VERSION 5.4 ;
NAMESCASESENSITIVE ON ;
BUSBITCHARS "[]" ;
DIVIDERCHAR "/" ;
UNITS
  DATABASE MICRONS 2000 ;
END UNITS
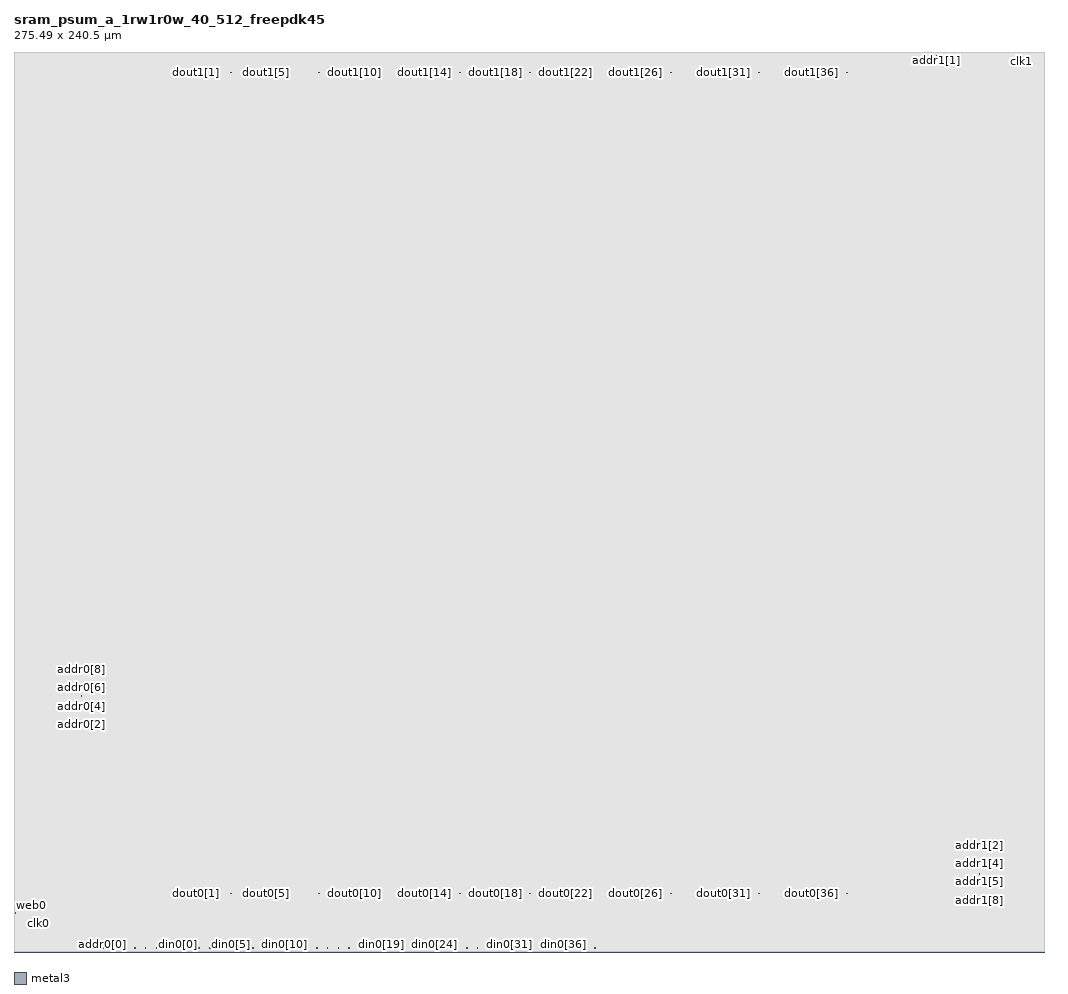
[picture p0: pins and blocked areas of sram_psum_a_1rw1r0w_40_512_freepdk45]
MACRO sram_psum_a_1rw1r0w_40_512_freepdk45
   CLASS BLOCK ;
   SIZE 275.49 BY 240.5 ;
   SYMMETRY X Y R90 ;
   PIN din0[0]
      DIRECTION INPUT ;
      PORT
         LAYER metal3 ;
         RECT 43.715 1.04 43.85 1.175 ;
      END
   END din0[0]
   PIN din0[1]
      DIRECTION INPUT ;
      PORT
         LAYER metal3 ;
         RECT 46.575 1.04 46.71 1.175 ;
      END
   END din0[1]
   PIN din0[2]
      DIRECTION INPUT ;
      PORT
         LAYER metal3 ;
         RECT 49.435 1.04 49.57 1.175 ;
      END
   END din0[2]
   PIN din0[3]
      DIRECTION INPUT ;
      PORT
         LAYER metal3 ;
         RECT 52.295 1.04 52.43 1.175 ;
      END
   END din0[3]
   PIN din0[4]
      DIRECTION INPUT ;
      PORT
         LAYER metal3 ;
         RECT 55.155 1.04 55.29 1.175 ;
      END
   END din0[4]
   PIN din0[5]
      DIRECTION INPUT ;
      PORT
         LAYER metal3 ;
         RECT 58.015 1.04 58.15 1.175 ;
      END
   END din0[5]
   PIN din0[6]
      DIRECTION INPUT ;
      PORT
         LAYER metal3 ;
         RECT 60.875 1.04 61.01 1.175 ;
      END
   END din0[6]
   PIN din0[7]
      DIRECTION INPUT ;
      PORT
         LAYER metal3 ;
         RECT 63.735 1.04 63.87 1.175 ;
      END
   END din0[7]
   PIN din0[8]
      DIRECTION INPUT ;
      PORT
         LAYER metal3 ;
         RECT 66.595 1.04 66.73 1.175 ;
      END
   END din0[8]
   PIN din0[9]
      DIRECTION INPUT ;
      PORT
         LAYER metal3 ;
         RECT 69.455 1.04 69.59 1.175 ;
      END
   END din0[9]
   PIN din0[10]
      DIRECTION INPUT ;
      PORT
         LAYER metal3 ;
         RECT 72.315 1.04 72.45 1.175 ;
      END
   END din0[10]
   PIN din0[11]
      DIRECTION INPUT ;
      PORT
         LAYER metal3 ;
         RECT 75.175 1.04 75.31 1.175 ;
      END
   END din0[11]
   PIN din0[12]
      DIRECTION INPUT ;
      PORT
         LAYER metal3 ;
         RECT 78.035 1.04 78.17 1.175 ;
      END
   END din0[12]
   PIN din0[13]
      DIRECTION INPUT ;
      PORT
         LAYER metal3 ;
         RECT 80.895 1.04 81.03 1.175 ;
      END
   END din0[13]
   PIN din0[14]
      DIRECTION INPUT ;
      PORT
         LAYER metal3 ;
         RECT 83.755 1.04 83.89 1.175 ;
      END
   END din0[14]
   PIN din0[15]
      DIRECTION INPUT ;
      PORT
         LAYER metal3 ;
         RECT 86.615 1.04 86.75 1.175 ;
      END
   END din0[15]
   PIN din0[16]
      DIRECTION INPUT ;
      PORT
         LAYER metal3 ;
         RECT 89.475 1.04 89.61 1.175 ;
      END
   END din0[16]
   PIN din0[17]
      DIRECTION INPUT ;
      PORT
         LAYER metal3 ;
         RECT 92.335 1.04 92.47 1.175 ;
      END
   END din0[17]
   PIN din0[18]
      DIRECTION INPUT ;
      PORT
         LAYER metal3 ;
         RECT 95.195 1.04 95.33 1.175 ;
      END
   END din0[18]
   PIN din0[19]
      DIRECTION INPUT ;
      PORT
         LAYER metal3 ;
         RECT 98.055 1.04 98.19 1.175 ;
      END
   END din0[19]
   PIN din0[20]
      DIRECTION INPUT ;
      PORT
         LAYER metal3 ;
         RECT 100.915 1.04 101.05 1.175 ;
      END
   END din0[20]
   PIN din0[21]
      DIRECTION INPUT ;
      PORT
         LAYER metal3 ;
         RECT 103.775 1.04 103.91 1.175 ;
      END
   END din0[21]
   PIN din0[22]
      DIRECTION INPUT ;
      PORT
         LAYER metal3 ;
         RECT 106.635 1.04 106.77 1.175 ;
      END
   END din0[22]
   PIN din0[23]
      DIRECTION INPUT ;
      PORT
         LAYER metal3 ;
         RECT 109.495 1.04 109.63 1.175 ;
      END
   END din0[23]
   PIN din0[24]
      DIRECTION INPUT ;
      PORT
         LAYER metal3 ;
         RECT 112.355 1.04 112.49 1.175 ;
      END
   END din0[24]
   PIN din0[25]
      DIRECTION INPUT ;
      PORT
         LAYER metal3 ;
         RECT 115.215 1.04 115.35 1.175 ;
      END
   END din0[25]
   PIN din0[26]
      DIRECTION INPUT ;
      PORT
         LAYER metal3 ;
         RECT 118.075 1.04 118.21 1.175 ;
      END
   END din0[26]
   PIN din0[27]
      DIRECTION INPUT ;
      PORT
         LAYER metal3 ;
         RECT 120.935 1.04 121.07 1.175 ;
      END
   END din0[27]
   PIN din0[28]
      DIRECTION INPUT ;
      PORT
         LAYER metal3 ;
         RECT 123.795 1.04 123.93 1.175 ;
      END
   END din0[28]
   PIN din0[29]
      DIRECTION INPUT ;
      PORT
         LAYER metal3 ;
         RECT 126.655 1.04 126.79 1.175 ;
      END
   END din0[29]
   PIN din0[30]
      DIRECTION INPUT ;
      PORT
         LAYER metal3 ;
         RECT 129.515 1.04 129.65 1.175 ;
      END
   END din0[30]
   PIN din0[31]
      DIRECTION INPUT ;
      PORT
         LAYER metal3 ;
         RECT 132.375 1.04 132.51 1.175 ;
      END
   END din0[31]
   PIN din0[32]
      DIRECTION INPUT ;
      PORT
         LAYER metal3 ;
         RECT 135.235 1.04 135.37 1.175 ;
      END
   END din0[32]
   PIN din0[33]
      DIRECTION INPUT ;
      PORT
         LAYER metal3 ;
         RECT 138.095 1.04 138.23 1.175 ;
      END
   END din0[33]
   PIN din0[34]
      DIRECTION INPUT ;
      PORT
         LAYER metal3 ;
         RECT 140.955 1.04 141.09 1.175 ;
      END
   END din0[34]
   PIN din0[35]
      DIRECTION INPUT ;
      PORT
         LAYER metal3 ;
         RECT 143.815 1.04 143.95 1.175 ;
      END
   END din0[35]
   PIN din0[36]
      DIRECTION INPUT ;
      PORT
         LAYER metal3 ;
         RECT 146.675 1.04 146.81 1.175 ;
      END
   END din0[36]
   PIN din0[37]
      DIRECTION INPUT ;
      PORT
         LAYER metal3 ;
         RECT 149.535 1.04 149.67 1.175 ;
      END
   END din0[37]
   PIN din0[38]
      DIRECTION INPUT ;
      PORT
         LAYER metal3 ;
         RECT 152.395 1.04 152.53 1.175 ;
      END
   END din0[38]
   PIN din0[39]
      DIRECTION INPUT ;
      PORT
         LAYER metal3 ;
         RECT 155.255 1.04 155.39 1.175 ;
      END
   END din0[39]
   PIN addr0[0]
      DIRECTION INPUT ;
      PORT
         LAYER metal3 ;
         RECT 23.695 1.04 23.83 1.175 ;
      END
   END addr0[0]
   PIN addr0[1]
      DIRECTION INPUT ;
      PORT
         LAYER metal3 ;
         RECT 26.555 1.04 26.69 1.175 ;
      END
   END addr0[1]
   PIN addr0[2]
      DIRECTION INPUT ;
      PORT
         LAYER metal3 ;
         RECT 17.975 60.615 18.11 60.75 ;
      END
   END addr0[2]
   PIN addr0[3]
      DIRECTION INPUT ;
      PORT
         LAYER metal3 ;
         RECT 17.975 63.345 18.11 63.48 ;
      END
   END addr0[3]
   PIN addr0[4]
      DIRECTION INPUT ;
      PORT
         LAYER metal3 ;
         RECT 17.975 65.555 18.11 65.69 ;
      END
   END addr0[4]
   PIN addr0[5]
      DIRECTION INPUT ;
      PORT
         LAYER metal3 ;
         RECT 17.975 68.285 18.11 68.42 ;
      END
   END addr0[5]
   PIN addr0[6]
      DIRECTION INPUT ;
      PORT
         LAYER metal3 ;
         RECT 17.975 70.495 18.11 70.63 ;
      END
   END addr0[6]
   PIN addr0[7]
      DIRECTION INPUT ;
      PORT
         LAYER metal3 ;
         RECT 17.975 73.225 18.11 73.36 ;
      END
   END addr0[7]
   PIN addr0[8]
      DIRECTION INPUT ;
      PORT
         LAYER metal3 ;
         RECT 17.975 75.435 18.11 75.57 ;
      END
   END addr0[8]
   PIN addr1[0]
      DIRECTION INPUT ;
      PORT
         LAYER metal3 ;
         RECT 249.355 239.33 249.49 239.465 ;
      END
   END addr1[0]
   PIN addr1[1]
      DIRECTION INPUT ;
      PORT
         LAYER metal3 ;
         RECT 246.495 239.33 246.63 239.465 ;
      END
   END addr1[1]
   PIN addr1[2]
      DIRECTION INPUT ;
      PORT
         LAYER metal3 ;
         RECT 257.935 28.505 258.07 28.64 ;
      END
   END addr1[2]
   PIN addr1[3]
      DIRECTION INPUT ;
      PORT
         LAYER metal3 ;
         RECT 257.935 25.775 258.07 25.91 ;
      END
   END addr1[3]
   PIN addr1[4]
      DIRECTION INPUT ;
      PORT
         LAYER metal3 ;
         RECT 257.935 23.565 258.07 23.7 ;
      END
   END addr1[4]
   PIN addr1[5]
      DIRECTION INPUT ;
      PORT
         LAYER metal3 ;
         RECT 257.935 20.835 258.07 20.97 ;
      END
   END addr1[5]
   PIN addr1[6]
      DIRECTION INPUT ;
      PORT
         LAYER metal3 ;
         RECT 257.935 18.625 258.07 18.76 ;
      END
   END addr1[6]
   PIN addr1[7]
      DIRECTION INPUT ;
      PORT
         LAYER metal3 ;
         RECT 257.935 15.895 258.07 16.03 ;
      END
   END addr1[7]
   PIN addr1[8]
      DIRECTION INPUT ;
      PORT
         LAYER metal3 ;
         RECT 257.935 13.685 258.07 13.82 ;
      END
   END addr1[8]
   PIN csb0
      DIRECTION INPUT ;
      PORT
         LAYER metal3 ;
         RECT 0.285 7.575 0.42 7.71 ;
      END
   END csb0
   PIN csb1
      DIRECTION INPUT ;
      PORT
         LAYER metal3 ;
         RECT 275.07 237.885 275.205 238.02 ;
      END
   END csb1
   PIN web0
      DIRECTION INPUT ;
      PORT
         LAYER metal3 ;
         RECT 0.285 10.305 0.42 10.44 ;
      END
   END web0
   PIN clk0
      DIRECTION INPUT ;
      PORT
         LAYER metal3 ;
         RECT 6.53 7.66 6.66 7.795 ;
      END
   END clk0
   PIN clk1
      DIRECTION INPUT ;
      PORT
         LAYER metal3 ;
         RECT 269.11 237.8 269.24 237.935 ;
      END
   END clk1
   PIN wmask0[0]
      DIRECTION INPUT ;
      PORT
         LAYER metal3 ;
         RECT 29.415 1.04 29.55 1.175 ;
      END
   END wmask0[0]
   PIN wmask0[1]
      DIRECTION INPUT ;
      PORT
         LAYER metal3 ;
         RECT 32.275 1.04 32.41 1.175 ;
      END
   END wmask0[1]
   PIN wmask0[2]
      DIRECTION INPUT ;
      PORT
         LAYER metal3 ;
         RECT 35.135 1.04 35.27 1.175 ;
      END
   END wmask0[2]
   PIN wmask0[3]
      DIRECTION INPUT ;
      PORT
         LAYER metal3 ;
         RECT 37.995 1.04 38.13 1.175 ;
      END
   END wmask0[3]
   PIN wmask0[4]
      DIRECTION INPUT ;
      PORT
         LAYER metal3 ;
         RECT 40.855 1.04 40.99 1.175 ;
      END
   END wmask0[4]
   PIN dout0[0]
      DIRECTION OUTPUT ;
      PORT
         LAYER metal3 ;
         RECT 43.885 15.5 44.02 15.64 ;
      END
   END dout0[0]
   PIN dout0[1]
      DIRECTION OUTPUT ;
      PORT
         LAYER metal3 ;
         RECT 48.585 15.5 48.72 15.64 ;
      END
   END dout0[1]
   PIN dout0[2]
      DIRECTION OUTPUT ;
      PORT
         LAYER metal3 ;
         RECT 53.285 15.5 53.42 15.64 ;
      END
   END dout0[2]
   PIN dout0[3]
      DIRECTION OUTPUT ;
      PORT
         LAYER metal3 ;
         RECT 57.985 15.5 58.12 15.64 ;
      END
   END dout0[3]
   PIN dout0[4]
      DIRECTION OUTPUT ;
      PORT
         LAYER metal3 ;
         RECT 62.685 15.5 62.82 15.64 ;
      END
   END dout0[4]
   PIN dout0[5]
      DIRECTION OUTPUT ;
      PORT
         LAYER metal3 ;
         RECT 67.385 15.5 67.52 15.64 ;
      END
   END dout0[5]
   PIN dout0[6]
      DIRECTION OUTPUT ;
      PORT
         LAYER metal3 ;
         RECT 72.085 15.5 72.22 15.64 ;
      END
   END dout0[6]
   PIN dout0[7]
      DIRECTION OUTPUT ;
      PORT
         LAYER metal3 ;
         RECT 76.785 15.5 76.92 15.64 ;
      END
   END dout0[7]
   PIN dout0[8]
      DIRECTION OUTPUT ;
      PORT
         LAYER metal3 ;
         RECT 81.485 15.5 81.62 15.64 ;
      END
   END dout0[8]
   PIN dout0[9]
      DIRECTION OUTPUT ;
      PORT
         LAYER metal3 ;
         RECT 86.185 15.5 86.32 15.64 ;
      END
   END dout0[9]
   PIN dout0[10]
      DIRECTION OUTPUT ;
      PORT
         LAYER metal3 ;
         RECT 90.885 15.5 91.02 15.64 ;
      END
   END dout0[10]
   PIN dout0[11]
      DIRECTION OUTPUT ;
      PORT
         LAYER metal3 ;
         RECT 95.585 15.5 95.72 15.64 ;
      END
   END dout0[11]
   PIN dout0[12]
      DIRECTION OUTPUT ;
      PORT
         LAYER metal3 ;
         RECT 100.285 15.5 100.42 15.64 ;
      END
   END dout0[12]
   PIN dout0[13]
      DIRECTION OUTPUT ;
      PORT
         LAYER metal3 ;
         RECT 104.985 15.5 105.12 15.64 ;
      END
   END dout0[13]
   PIN dout0[14]
      DIRECTION OUTPUT ;
      PORT
         LAYER metal3 ;
         RECT 109.685 15.5 109.82 15.64 ;
      END
   END dout0[14]
   PIN dout0[15]
      DIRECTION OUTPUT ;
      PORT
         LAYER metal3 ;
         RECT 114.385 15.5 114.52 15.64 ;
      END
   END dout0[15]
   PIN dout0[16]
      DIRECTION OUTPUT ;
      PORT
         LAYER metal3 ;
         RECT 119.085 15.5 119.22 15.64 ;
      END
   END dout0[16]
   PIN dout0[17]
      DIRECTION OUTPUT ;
      PORT
         LAYER metal3 ;
         RECT 123.785 15.5 123.92 15.64 ;
      END
   END dout0[17]
   PIN dout0[18]
      DIRECTION OUTPUT ;
      PORT
         LAYER metal3 ;
         RECT 128.485 15.5 128.62 15.64 ;
      END
   END dout0[18]
   PIN dout0[19]
      DIRECTION OUTPUT ;
      PORT
         LAYER metal3 ;
         RECT 133.185 15.5 133.32 15.64 ;
      END
   END dout0[19]
   PIN dout0[20]
      DIRECTION OUTPUT ;
      PORT
         LAYER metal3 ;
         RECT 137.885 15.5 138.02 15.64 ;
      END
   END dout0[20]
   PIN dout0[21]
      DIRECTION OUTPUT ;
      PORT
         LAYER metal3 ;
         RECT 142.585 15.5 142.72 15.64 ;
      END
   END dout0[21]
   PIN dout0[22]
      DIRECTION OUTPUT ;
      PORT
         LAYER metal3 ;
         RECT 147.285 15.5 147.42 15.64 ;
      END
   END dout0[22]
   PIN dout0[23]
      DIRECTION OUTPUT ;
      PORT
         LAYER metal3 ;
         RECT 151.985 15.5 152.12 15.64 ;
      END
   END dout0[23]
   PIN dout0[24]
      DIRECTION OUTPUT ;
      PORT
         LAYER metal3 ;
         RECT 156.685 15.5 156.82 15.64 ;
      END
   END dout0[24]
   PIN dout0[25]
      DIRECTION OUTPUT ;
      PORT
         LAYER metal3 ;
         RECT 161.385 15.5 161.52 15.64 ;
      END
   END dout0[25]
   PIN dout0[26]
      DIRECTION OUTPUT ;
      PORT
         LAYER metal3 ;
         RECT 166.085 15.5 166.22 15.64 ;
      END
   END dout0[26]
   PIN dout0[27]
      DIRECTION OUTPUT ;
      PORT
         LAYER metal3 ;
         RECT 170.785 15.5 170.92 15.64 ;
      END
   END dout0[27]
   PIN dout0[28]
      DIRECTION OUTPUT ;
      PORT
         LAYER metal3 ;
         RECT 175.485 15.5 175.62 15.64 ;
      END
   END dout0[28]
   PIN dout0[29]
      DIRECTION OUTPUT ;
      PORT
         LAYER metal3 ;
         RECT 180.185 15.5 180.32 15.64 ;
      END
   END dout0[29]
   PIN dout0[30]
      DIRECTION OUTPUT ;
      PORT
         LAYER metal3 ;
         RECT 184.885 15.5 185.02 15.64 ;
      END
   END dout0[30]
   PIN dout0[31]
      DIRECTION OUTPUT ;
      PORT
         LAYER metal3 ;
         RECT 189.585 15.5 189.72 15.64 ;
      END
   END dout0[31]
   PIN dout0[32]
      DIRECTION OUTPUT ;
      PORT
         LAYER metal3 ;
         RECT 194.285 15.5 194.42 15.64 ;
      END
   END dout0[32]
   PIN dout0[33]
      DIRECTION OUTPUT ;
      PORT
         LAYER metal3 ;
         RECT 198.985 15.5 199.12 15.64 ;
      END
   END dout0[33]
   PIN dout0[34]
      DIRECTION OUTPUT ;
      PORT
         LAYER metal3 ;
         RECT 203.685 15.5 203.82 15.64 ;
      END
   END dout0[34]
   PIN dout0[35]
      DIRECTION OUTPUT ;
      PORT
         LAYER metal3 ;
         RECT 208.385 15.5 208.52 15.64 ;
      END
   END dout0[35]
   PIN dout0[36]
      DIRECTION OUTPUT ;
      PORT
         LAYER metal3 ;
         RECT 213.085 15.5 213.22 15.64 ;
      END
   END dout0[36]
   PIN dout0[37]
      DIRECTION OUTPUT ;
      PORT
         LAYER metal3 ;
         RECT 217.785 15.5 217.92 15.64 ;
      END
   END dout0[37]
   PIN dout0[38]
      DIRECTION OUTPUT ;
      PORT
         LAYER metal3 ;
         RECT 222.485 15.5 222.62 15.64 ;
      END
   END dout0[38]
   PIN dout0[39]
      DIRECTION OUTPUT ;
      PORT
         LAYER metal3 ;
         RECT 227.185 15.5 227.32 15.64 ;
      END
   END dout0[39]
   PIN dout1[0]
      DIRECTION OUTPUT ;
      PORT
         LAYER metal3 ;
         RECT 43.885 234.9 44.02 235.03 ;
      END
   END dout1[0]
   PIN dout1[1]
      DIRECTION OUTPUT ;
      PORT
         LAYER metal3 ;
         RECT 48.585 234.9 48.72 235.03 ;
      END
   END dout1[1]
   PIN dout1[2]
      DIRECTION OUTPUT ;
      PORT
         LAYER metal3 ;
         RECT 53.285 234.9 53.42 235.03 ;
      END
   END dout1[2]
   PIN dout1[3]
      DIRECTION OUTPUT ;
      PORT
         LAYER metal3 ;
         RECT 57.985 234.9 58.12 235.03 ;
      END
   END dout1[3]
   PIN dout1[4]
      DIRECTION OUTPUT ;
      PORT
         LAYER metal3 ;
         RECT 62.685 234.9 62.82 235.03 ;
      END
   END dout1[4]
   PIN dout1[5]
      DIRECTION OUTPUT ;
      PORT
         LAYER metal3 ;
         RECT 67.385 234.9 67.52 235.03 ;
      END
   END dout1[5]
   PIN dout1[6]
      DIRECTION OUTPUT ;
      PORT
         LAYER metal3 ;
         RECT 72.085 234.9 72.22 235.03 ;
      END
   END dout1[6]
   PIN dout1[7]
      DIRECTION OUTPUT ;
      PORT
         LAYER metal3 ;
         RECT 76.785 234.9 76.92 235.03 ;
      END
   END dout1[7]
   PIN dout1[8]
      DIRECTION OUTPUT ;
      PORT
         LAYER metal3 ;
         RECT 81.485 234.9 81.62 235.03 ;
      END
   END dout1[8]
   PIN dout1[9]
      DIRECTION OUTPUT ;
      PORT
         LAYER metal3 ;
         RECT 86.185 234.9 86.32 235.03 ;
      END
   END dout1[9]
   PIN dout1[10]
      DIRECTION OUTPUT ;
      PORT
         LAYER metal3 ;
         RECT 90.885 234.9 91.02 235.03 ;
      END
   END dout1[10]
   PIN dout1[11]
      DIRECTION OUTPUT ;
      PORT
         LAYER metal3 ;
         RECT 95.585 234.9 95.72 235.03 ;
      END
   END dout1[11]
   PIN dout1[12]
      DIRECTION OUTPUT ;
      PORT
         LAYER metal3 ;
         RECT 100.285 234.9 100.42 235.03 ;
      END
   END dout1[12]
   PIN dout1[13]
      DIRECTION OUTPUT ;
      PORT
         LAYER metal3 ;
         RECT 104.985 234.9 105.12 235.03 ;
      END
   END dout1[13]
   PIN dout1[14]
      DIRECTION OUTPUT ;
      PORT
         LAYER metal3 ;
         RECT 109.685 234.9 109.82 235.03 ;
      END
   END dout1[14]
   PIN dout1[15]
      DIRECTION OUTPUT ;
      PORT
         LAYER metal3 ;
         RECT 114.385 234.9 114.52 235.03 ;
      END
   END dout1[15]
   PIN dout1[16]
      DIRECTION OUTPUT ;
      PORT
         LAYER metal3 ;
         RECT 119.085 234.9 119.22 235.03 ;
      END
   END dout1[16]
   PIN dout1[17]
      DIRECTION OUTPUT ;
      PORT
         LAYER metal3 ;
         RECT 123.785 234.9 123.92 235.03 ;
      END
   END dout1[17]
   PIN dout1[18]
      DIRECTION OUTPUT ;
      PORT
         LAYER metal3 ;
         RECT 128.485 234.9 128.62 235.03 ;
      END
   END dout1[18]
   PIN dout1[19]
      DIRECTION OUTPUT ;
      PORT
         LAYER metal3 ;
         RECT 133.185 234.9 133.32 235.03 ;
      END
   END dout1[19]
   PIN dout1[20]
      DIRECTION OUTPUT ;
      PORT
         LAYER metal3 ;
         RECT 137.885 234.9 138.02 235.03 ;
      END
   END dout1[20]
   PIN dout1[21]
      DIRECTION OUTPUT ;
      PORT
         LAYER metal3 ;
         RECT 142.585 234.9 142.72 235.03 ;
      END
   END dout1[21]
   PIN dout1[22]
      DIRECTION OUTPUT ;
      PORT
         LAYER metal3 ;
         RECT 147.285 234.9 147.42 235.03 ;
      END
   END dout1[22]
   PIN dout1[23]
      DIRECTION OUTPUT ;
      PORT
         LAYER metal3 ;
         RECT 151.985 234.9 152.12 235.03 ;
      END
   END dout1[23]
   PIN dout1[24]
      DIRECTION OUTPUT ;
      PORT
         LAYER metal3 ;
         RECT 156.685 234.9 156.82 235.03 ;
      END
   END dout1[24]
   PIN dout1[25]
      DIRECTION OUTPUT ;
      PORT
         LAYER metal3 ;
         RECT 161.385 234.9 161.52 235.03 ;
      END
   END dout1[25]
   PIN dout1[26]
      DIRECTION OUTPUT ;
      PORT
         LAYER metal3 ;
         RECT 166.085 234.9 166.22 235.03 ;
      END
   END dout1[26]
   PIN dout1[27]
      DIRECTION OUTPUT ;
      PORT
         LAYER metal3 ;
         RECT 170.785 234.9 170.92 235.03 ;
      END
   END dout1[27]
   PIN dout1[28]
      DIRECTION OUTPUT ;
      PORT
         LAYER metal3 ;
         RECT 175.485 234.9 175.62 235.03 ;
      END
   END dout1[28]
   PIN dout1[29]
      DIRECTION OUTPUT ;
      PORT
         LAYER metal3 ;
         RECT 180.185 234.9 180.32 235.03 ;
      END
   END dout1[29]
   PIN dout1[30]
      DIRECTION OUTPUT ;
      PORT
         LAYER metal3 ;
         RECT 184.885 234.9 185.02 235.03 ;
      END
   END dout1[30]
   PIN dout1[31]
      DIRECTION OUTPUT ;
      PORT
         LAYER metal3 ;
         RECT 189.585 234.9 189.72 235.03 ;
      END
   END dout1[31]
   PIN dout1[32]
      DIRECTION OUTPUT ;
      PORT
         LAYER metal3 ;
         RECT 194.285 234.9 194.42 235.03 ;
      END
   END dout1[32]
   PIN dout1[33]
      DIRECTION OUTPUT ;
      PORT
         LAYER metal3 ;
         RECT 198.985 234.9 199.12 235.03 ;
      END
   END dout1[33]
   PIN dout1[34]
      DIRECTION OUTPUT ;
      PORT
         LAYER metal3 ;
         RECT 203.685 234.9 203.82 235.03 ;
      END
   END dout1[34]
   PIN dout1[35]
      DIRECTION OUTPUT ;
      PORT
         LAYER metal3 ;
         RECT 208.385 234.9 208.52 235.03 ;
      END
   END dout1[35]
   PIN dout1[36]
      DIRECTION OUTPUT ;
      PORT
         LAYER metal3 ;
         RECT 213.085 234.9 213.22 235.03 ;
      END
   END dout1[36]
   PIN dout1[37]
      DIRECTION OUTPUT ;
      PORT
         LAYER metal3 ;
         RECT 217.785 234.9 217.92 235.03 ;
      END
   END dout1[37]
   PIN dout1[38]
      DIRECTION OUTPUT ;
      PORT
         LAYER metal3 ;
         RECT 222.485 234.9 222.62 235.03 ;
      END
   END dout1[38]
   PIN dout1[39]
      DIRECTION OUTPUT ;
      PORT
         LAYER metal3 ;
         RECT 227.185 234.9 227.32 235.03 ;
      END
   END dout1[39]
   PIN vdd
      DIRECTION INOUT ;
      USE POWER ; 
      SHAPE ABUTMENT ; 
      PORT
      END
   END vdd
   PIN gnd
      DIRECTION INOUT ;
      USE GROUND ; 
      SHAPE ABUTMENT ; 
      PORT
      END
   END gnd
   OBS
   LAYER  metal1 ;
      RECT 0.14 0.14 275.35 240.36 ;
   LAYER  metal2 ;
      RECT 0.14 0.14 275.35 240.36 ;
   LAYER  metal3 ;
      RECT 0.14 0.14 43.575 0.9 ;
      RECT 43.575 0.14 43.99 0.9 ;
      RECT 43.99 0.14 275.35 0.9 ;
      RECT 43.99 0.9 46.435 1.31 ;
      RECT 46.85 0.9 49.295 1.31 ;
      RECT 49.71 0.9 52.155 1.31 ;
      RECT 52.57 0.9 55.015 1.31 ;
      RECT 55.43 0.9 57.875 1.31 ;
      RECT 58.29 0.9 60.735 1.31 ;
      RECT 61.15 0.9 63.595 1.31 ;
      RECT 64.01 0.9 66.455 1.31 ;
      RECT 66.87 0.9 69.315 1.31 ;
      RECT 69.73 0.9 72.175 1.31 ;
      RECT 72.59 0.9 75.035 1.31 ;
      RECT 75.45 0.9 77.895 1.31 ;
      RECT 78.31 0.9 80.755 1.31 ;
      RECT 81.17 0.9 83.615 1.31 ;
      RECT 84.03 0.9 86.475 1.31 ;
      RECT 86.89 0.9 89.335 1.31 ;
      RECT 89.75 0.9 92.195 1.31 ;
      RECT 92.61 0.9 95.055 1.31 ;
      RECT 95.47 0.9 97.915 1.31 ;
      RECT 98.33 0.9 100.775 1.31 ;
      RECT 101.19 0.9 103.635 1.31 ;
      RECT 104.05 0.9 106.495 1.31 ;
      RECT 106.91 0.9 109.355 1.31 ;
      RECT 109.77 0.9 112.215 1.31 ;
      RECT 112.63 0.9 115.075 1.31 ;
      RECT 115.49 0.9 117.935 1.31 ;
      RECT 118.35 0.9 120.795 1.31 ;
      RECT 121.21 0.9 123.655 1.31 ;
      RECT 124.07 0.9 126.515 1.31 ;
      RECT 126.93 0.9 129.375 1.31 ;
      RECT 129.79 0.9 132.235 1.31 ;
      RECT 132.65 0.9 135.095 1.31 ;
      RECT 135.51 0.9 137.955 1.31 ;
      RECT 138.37 0.9 140.815 1.31 ;
      RECT 141.23 0.9 143.675 1.31 ;
      RECT 144.09 0.9 146.535 1.31 ;
      RECT 146.95 0.9 149.395 1.31 ;
      RECT 149.81 0.9 152.255 1.31 ;
      RECT 152.67 0.9 155.115 1.31 ;
      RECT 155.53 0.9 275.35 1.31 ;
      RECT 0.14 0.9 23.555 1.31 ;
      RECT 23.97 0.9 26.415 1.31 ;
      RECT 0.14 60.475 17.835 60.89 ;
      RECT 0.14 60.89 17.835 240.36 ;
      RECT 17.835 1.31 18.25 60.475 ;
      RECT 18.25 1.31 43.575 60.475 ;
      RECT 18.25 60.475 43.575 60.89 ;
      RECT 18.25 60.89 43.575 240.36 ;
      RECT 17.835 60.89 18.25 63.205 ;
      RECT 17.835 63.62 18.25 65.415 ;
      RECT 17.835 65.83 18.25 68.145 ;
      RECT 17.835 68.56 18.25 70.355 ;
      RECT 17.835 70.77 18.25 73.085 ;
      RECT 17.835 73.5 18.25 75.295 ;
      RECT 17.835 75.71 18.25 240.36 ;
      RECT 43.99 239.605 249.215 240.36 ;
      RECT 249.215 1.31 249.63 239.19 ;
      RECT 249.215 239.605 249.63 240.36 ;
      RECT 249.63 239.19 275.35 239.605 ;
      RECT 249.63 239.605 275.35 240.36 ;
      RECT 43.99 239.19 246.355 239.605 ;
      RECT 246.77 239.19 249.215 239.605 ;
      RECT 249.63 1.31 257.795 28.365 ;
      RECT 249.63 28.365 257.795 28.78 ;
      RECT 249.63 28.78 257.795 239.19 ;
      RECT 257.795 28.78 258.21 239.19 ;
      RECT 258.21 1.31 275.35 28.365 ;
      RECT 258.21 28.365 275.35 28.78 ;
      RECT 257.795 26.05 258.21 28.365 ;
      RECT 257.795 23.84 258.21 25.635 ;
      RECT 257.795 21.11 258.21 23.425 ;
      RECT 257.795 18.9 258.21 20.695 ;
      RECT 257.795 16.17 258.21 18.485 ;
      RECT 257.795 1.31 258.21 13.545 ;
      RECT 257.795 13.96 258.21 15.755 ;
      RECT 0.14 1.31 0.145 7.435 ;
      RECT 0.14 7.435 0.145 7.85 ;
      RECT 0.14 7.85 0.145 60.475 ;
      RECT 0.145 1.31 0.56 7.435 ;
      RECT 0.56 1.31 17.835 7.435 ;
      RECT 258.21 238.16 274.93 239.19 ;
      RECT 274.93 28.78 275.345 237.745 ;
      RECT 274.93 238.16 275.345 239.19 ;
      RECT 275.345 28.78 275.35 237.745 ;
      RECT 275.345 237.745 275.35 238.16 ;
      RECT 275.345 238.16 275.35 239.19 ;
      RECT 0.145 7.85 0.56 10.165 ;
      RECT 0.145 10.58 0.56 60.475 ;
      RECT 0.56 7.435 6.39 7.52 ;
      RECT 0.56 7.52 6.39 7.85 ;
      RECT 6.39 7.435 6.8 7.52 ;
      RECT 6.8 7.435 17.835 7.52 ;
      RECT 6.8 7.52 17.835 7.85 ;
      RECT 0.56 7.85 6.39 7.935 ;
      RECT 0.56 7.935 6.39 60.475 ;
      RECT 6.39 7.935 6.8 60.475 ;
      RECT 6.8 7.85 17.835 7.935 ;
      RECT 6.8 7.935 17.835 60.475 ;
      RECT 258.21 28.78 268.965 237.66 ;
      RECT 258.21 237.66 268.965 237.745 ;
      RECT 268.965 28.78 269.38 237.66 ;
      RECT 269.38 28.78 274.93 237.66 ;
      RECT 269.38 237.66 274.93 237.745 ;
      RECT 258.21 237.745 268.965 238.075 ;
      RECT 258.21 238.075 268.965 238.16 ;
      RECT 268.965 238.075 269.38 238.16 ;
      RECT 269.38 237.745 274.93 238.075 ;
      RECT 269.38 238.075 274.93 238.16 ;
      RECT 26.83 0.9 29.275 1.31 ;
      RECT 29.69 0.9 32.135 1.31 ;
      RECT 32.55 0.9 34.995 1.31 ;
      RECT 35.41 0.9 37.855 1.31 ;
      RECT 38.27 0.9 40.715 1.31 ;
      RECT 41.13 0.9 43.575 1.31 ;
      RECT 43.575 1.31 43.745 15.36 ;
      RECT 43.575 15.36 43.745 15.78 ;
      RECT 43.575 15.78 43.745 240.36 ;
      RECT 43.745 1.31 43.99 15.36 ;
      RECT 43.99 1.31 44.16 15.36 ;
      RECT 44.16 1.31 249.215 15.36 ;
      RECT 44.16 15.36 48.445 15.78 ;
      RECT 48.86 15.36 53.145 15.78 ;
      RECT 53.56 15.36 57.845 15.78 ;
      RECT 58.26 15.36 62.545 15.78 ;
      RECT 62.96 15.36 67.245 15.78 ;
      RECT 67.66 15.36 71.945 15.78 ;
      RECT 72.36 15.36 76.645 15.78 ;
      RECT 77.06 15.36 81.345 15.78 ;
      RECT 81.76 15.36 86.045 15.78 ;
      RECT 86.46 15.36 90.745 15.78 ;
      RECT 91.16 15.36 95.445 15.78 ;
      RECT 95.86 15.36 100.145 15.78 ;
      RECT 100.56 15.36 104.845 15.78 ;
      RECT 105.26 15.36 109.545 15.78 ;
      RECT 109.96 15.36 114.245 15.78 ;
      RECT 114.66 15.36 118.945 15.78 ;
      RECT 119.36 15.36 123.645 15.78 ;
      RECT 124.06 15.36 128.345 15.78 ;
      RECT 128.76 15.36 133.045 15.78 ;
      RECT 133.46 15.36 137.745 15.78 ;
      RECT 138.16 15.36 142.445 15.78 ;
      RECT 142.86 15.36 147.145 15.78 ;
      RECT 147.56 15.36 151.845 15.78 ;
      RECT 152.26 15.36 156.545 15.78 ;
      RECT 156.96 15.36 161.245 15.78 ;
      RECT 161.66 15.36 165.945 15.78 ;
      RECT 166.36 15.36 170.645 15.78 ;
      RECT 171.06 15.36 175.345 15.78 ;
      RECT 175.76 15.36 180.045 15.78 ;
      RECT 180.46 15.36 184.745 15.78 ;
      RECT 185.16 15.36 189.445 15.78 ;
      RECT 189.86 15.36 194.145 15.78 ;
      RECT 194.56 15.36 198.845 15.78 ;
      RECT 199.26 15.36 203.545 15.78 ;
      RECT 203.96 15.36 208.245 15.78 ;
      RECT 208.66 15.36 212.945 15.78 ;
      RECT 213.36 15.36 217.645 15.78 ;
      RECT 218.06 15.36 222.345 15.78 ;
      RECT 222.76 15.36 227.045 15.78 ;
      RECT 227.46 15.36 249.215 15.78 ;
      RECT 43.745 15.78 43.99 234.76 ;
      RECT 43.745 235.17 43.99 240.36 ;
      RECT 43.99 15.78 44.16 234.76 ;
      RECT 43.99 235.17 44.16 239.19 ;
      RECT 44.16 15.78 48.445 234.76 ;
      RECT 44.16 234.76 48.445 235.17 ;
      RECT 44.16 235.17 48.445 239.19 ;
      RECT 48.445 15.78 48.86 234.76 ;
      RECT 48.445 235.17 48.86 239.19 ;
      RECT 48.86 15.78 249.215 234.76 ;
      RECT 48.86 235.17 249.215 239.19 ;
      RECT 48.86 234.76 53.145 235.17 ;
      RECT 53.56 234.76 57.845 235.17 ;
      RECT 58.26 234.76 62.545 235.17 ;
      RECT 62.96 234.76 67.245 235.17 ;
      RECT 67.66 234.76 71.945 235.17 ;
      RECT 72.36 234.76 76.645 235.17 ;
      RECT 77.06 234.76 81.345 235.17 ;
      RECT 81.76 234.76 86.045 235.17 ;
      RECT 86.46 234.76 90.745 235.17 ;
      RECT 91.16 234.76 95.445 235.17 ;
      RECT 95.86 234.76 100.145 235.17 ;
      RECT 100.56 234.76 104.845 235.17 ;
      RECT 105.26 234.76 109.545 235.17 ;
      RECT 109.96 234.76 114.245 235.17 ;
      RECT 114.66 234.76 118.945 235.17 ;
      RECT 119.36 234.76 123.645 235.17 ;
      RECT 124.06 234.76 128.345 235.17 ;
      RECT 128.76 234.76 133.045 235.17 ;
      RECT 133.46 234.76 137.745 235.17 ;
      RECT 138.16 234.76 142.445 235.17 ;
      RECT 142.86 234.76 147.145 235.17 ;
      RECT 147.56 234.76 151.845 235.17 ;
      RECT 152.26 234.76 156.545 235.17 ;
      RECT 156.96 234.76 161.245 235.17 ;
      RECT 161.66 234.76 165.945 235.17 ;
      RECT 166.36 234.76 170.645 235.17 ;
      RECT 171.06 234.76 175.345 235.17 ;
      RECT 175.76 234.76 180.045 235.17 ;
      RECT 180.46 234.76 184.745 235.17 ;
      RECT 185.16 234.76 189.445 235.17 ;
      RECT 189.86 234.76 194.145 235.17 ;
      RECT 194.56 234.76 198.845 235.17 ;
      RECT 199.26 234.76 203.545 235.17 ;
      RECT 203.96 234.76 208.245 235.17 ;
      RECT 208.66 234.76 212.945 235.17 ;
      RECT 213.36 234.76 217.645 235.17 ;
      RECT 218.06 234.76 222.345 235.17 ;
      RECT 222.76 234.76 227.045 235.17 ;
      RECT 227.46 234.76 249.215 235.17 ;
   LAYER  metal4 ;
      RECT 0.14 0.14 275.35 240.36 ;
   END
END    sram_psum_a_1rw1r0w_40_512_freepdk45
END    LIBRARY
